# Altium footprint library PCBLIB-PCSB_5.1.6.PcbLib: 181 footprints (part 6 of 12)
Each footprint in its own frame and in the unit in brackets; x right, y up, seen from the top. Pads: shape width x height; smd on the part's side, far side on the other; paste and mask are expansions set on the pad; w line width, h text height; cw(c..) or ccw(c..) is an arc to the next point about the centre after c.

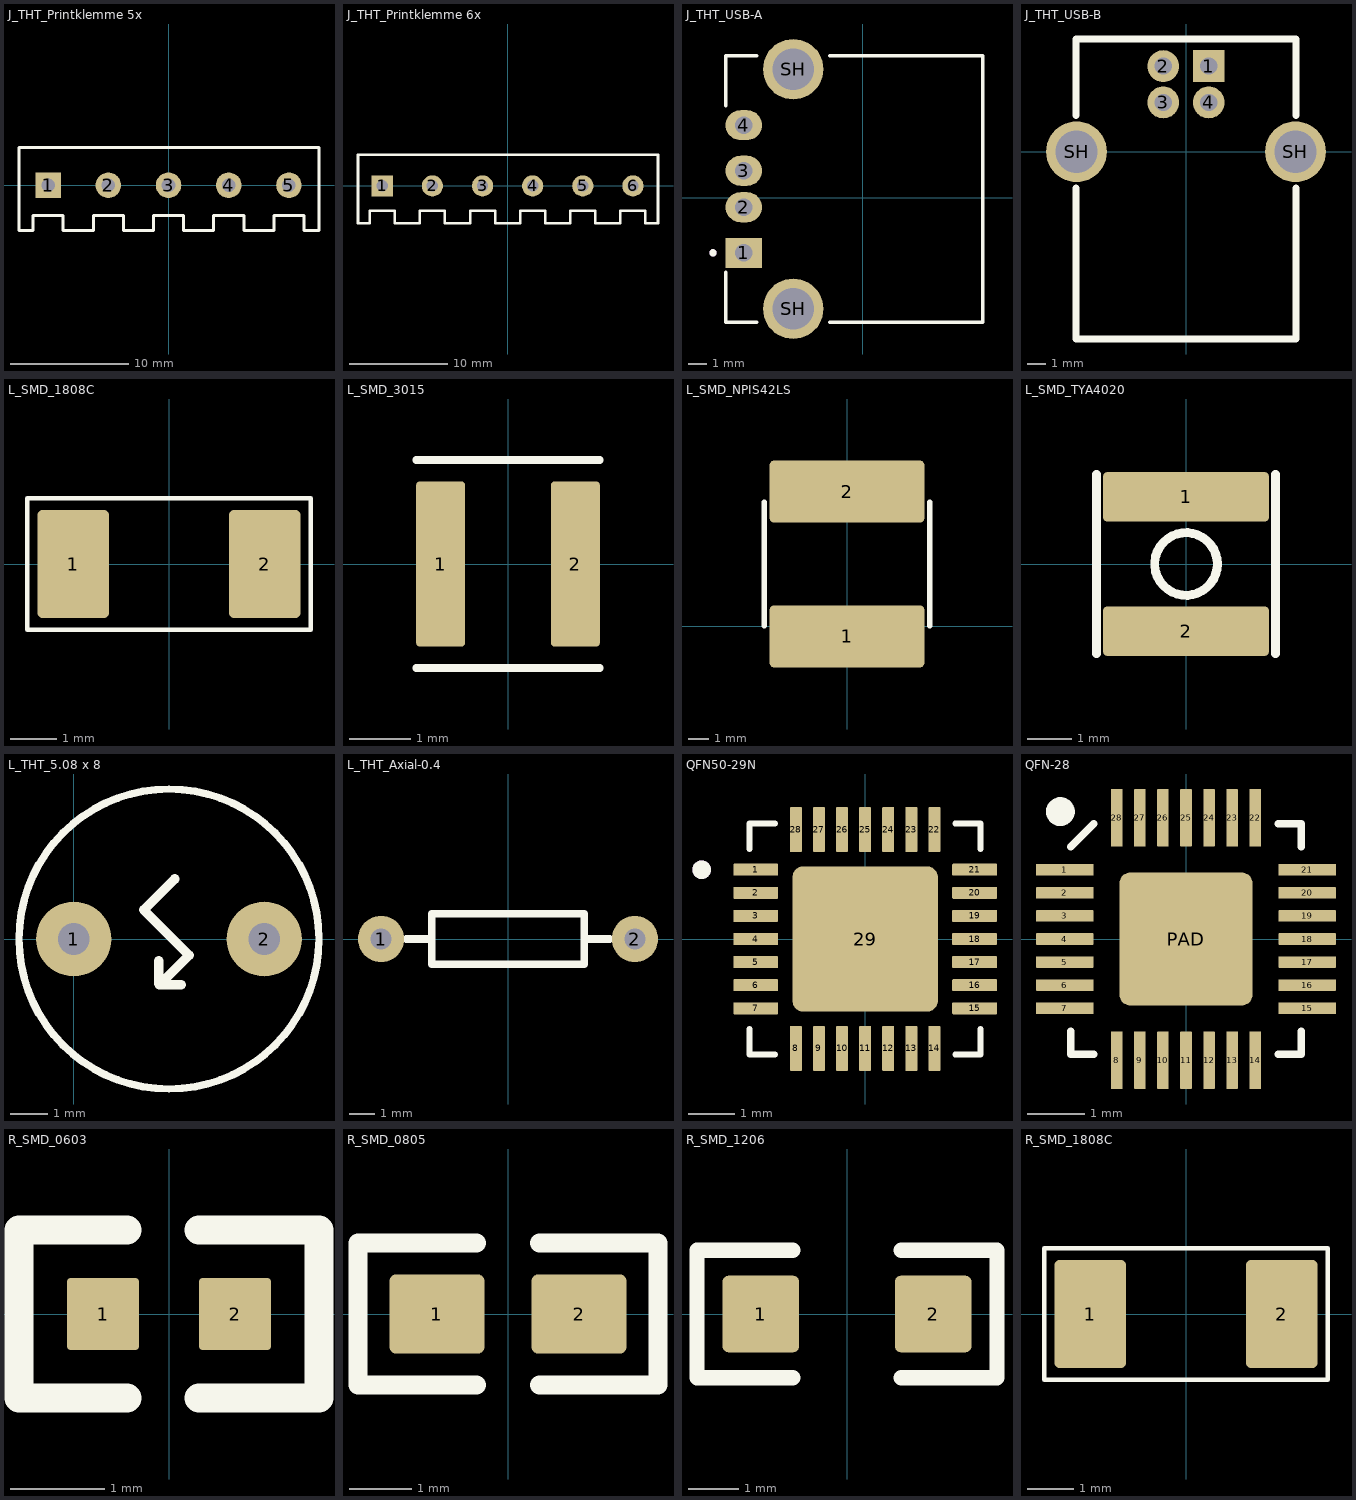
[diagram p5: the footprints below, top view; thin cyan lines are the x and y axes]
## J_THT_Printklemme 5x [mm] "LB-2024-04-17"
pads (5):
  rect 2.15x2.15 hole 1.15: 1(-10.16,0)
  round 2.15 hole 1.15: 2(-5.08,0) 3(0,0) 4(5.08,0) 5(10.16,0)
Top Overlay:
  lines w0.254: -6.35,-3.81 -6.35,-2.54 ; -6.35,-3.81 -8.89,-3.81 -8.89,-2.54 -11.43,-2.54 -11.43,-3.81 -12.62,-3.81 -12.62,2.365 -12.62,3.175 -2.43,3.175 12.7,3.175 12.7,-3.81 11.43,-3.81 11.43,-2.54 8.89,-2.54 8.89,-3.81 6.35,-3.81 6.35,-2.54 3.81,-2.54 3.81,-3.81 1.27,-3.81 1.27,-2.54 -1.27,-2.54 -1.27,-3.81 -3.81,-3.81 ; -6.35,-3.81 -6.35,-2.54 ; -6.35,-2.54 -3.81,-2.54 ; -3.81,-3.81 -3.81,-2.54 ; -3.81,-3.81 -3.81,-2.54

## J_THT_Printklemme 6x [mm] "LB-2024-04-17"
pads (6):
  rect 2.15x2.15 hole 1.15: 1(-12.7,0)
  round 2.15 hole 1.15: 2(-7.62,0) 3(-2.54,0) 4(2.54,0) 5(7.62,0) 6(12.7,0)
Top Overlay:
  lines w0.254: -8.89,-3.81 -8.89,-2.54 ; -8.89,-3.81 -11.43,-3.81 -11.43,-2.54 -13.97,-2.54 -13.97,-3.81 -15.16,-3.81 -15.16,2.365 -15.16,3.175 -4.97,3.175 15.24,3.175 15.24,-3.81 13.97,-3.81 13.97,-2.54 11.43,-2.54 11.43,-3.81 8.89,-3.81 8.89,-2.54 6.35,-2.54 6.35,-3.81 3.81,-3.81 3.81,-2.54 1.27,-2.54 1.27,-3.81 -1.27,-3.81 -1.27,-2.54 -3.81,-2.54 -3.81,-3.81 -6.35,-3.81 ; -8.89,-3.81 -8.89,-2.54 ; -8.89,-2.54 -6.35,-2.54 ; -6.35,-3.81 -6.35,-2.54 ; -6.35,-3.81 -6.35,-2.54

## J_THT_USB-A [mm] "LB-2024-04-29"
pads (6):
  rect 2x1.65 hole 0.95: 1(-6.536,-3.032)
  oval 2x1.65 hole 0.95: 2(-6.536,-0.532) 3(-6.536,1.468) 4(-6.536,3.968)
  round 3.316 hole 2.3: SH(-3.826,-6.102) SH(-3.826,7.038)
Top Overlay:
  circle w0.2: c-8.226,-3.032 r0.1
  lines w0.2: -7.526,-4.097 -7.526,-6.832 -5.836,-6.832 ; -7.526,5.033 -7.526,7.768 -5.836,7.768 ; -1.816,-6.832 6.574,-6.832 6.574,7.768 -1.816,7.768
Mechanical 13:
  circle w0.2: c-8.226,-3.032 r0.1

## J_THT_USB-B [mm] "LB-2024-04-15"
pads (6):
  rect 1.75x1.75 hole 0.95: 1(1.25,4.71)
  round 1.75 hole 0.95: 2(-1.25,4.71) 3(-1.25,2.71) 4(1.25,2.71)
  round 3.346 hole 2.33: SH(-6.02,0) SH(6.02,0)
Top Overlay:
  lines w0.4: -6.05,-2 -6.05,-10.3 6.05,-10.3 6.05,-2 ; -6.05,2 -6.05,6.2 6.05,6.2 6.05,2

## L_SMD_1808C [mm] "LB-2024-04-17"
height 2
pads (2):
  rrect15% 1.55x2.35 smd paste-0.02 mask+0.05: 1(-2.075,0) 2(2.075,0)
Top Overlay:
  lines w0.1: -3.075,-1.425 3.075,-1.425 3.075,1.425 -3.075,1.425 -3.075,-1.425

## L_SMD_3015 [mm] "LB-2024-09-01"
height 1.5
pads (2):
  rrect15% 0.8x2.7 smd paste-0.02 mask+0.05: 1(-1.1,0) 2(1.1,0)
Top Overlay:
  lines w0.127: -1.5,-1.7 1.5,-1.7 ; -1.5,1.7 1.5,1.7

## L_SMD_NPIS42LS [mm] "LB-2024-04-17"
pads (2):
  rrect15% 7.5x3 smd paste-0.02 mask+0.05: 1(0,-0.5) 2(0,6.5)
Top Overlay:
  lines w0.254: -4,0 -4,3 -4,6 ; 4,0 4,3 4,6

## L_SMD_TYA4020 [mm] "LB-2024-04-25"
height 2.1
pads (2):
  rrect15% 3.7x1.1 smd paste-0.02 mask+0.05: 1(0,1.5) 2(0,-1.5)
Top Overlay:
  circle w0.2: c0,0 r0.7
  lines w0.2: -2,-2 -2,0 -2,2 ; 2,-2 2,0 2,2

## L_THT_5.08 x 8 [mm] "LB-2024-04-17"
pads (2):
  round 2 hole 0.85: 1(0,0) 2(5.08,0)
Top Overlay:
  circle w0.2: c2.54,0 r4
  lines w0.254: 2.261,-0.762 2.261,-1.194 ; 2.261,-0.584 2.261,-1.194 ; 2.692,1.6 1.867,0.775 3.073,-0.432 2.286,-1.219 ; 2.261,-1.194 2.286,-1.219 ; 2.286,-1.219 2.87,-1.219 ; 2.286,-1.219 2.87,-1.219 ; 2.286,-1.219 2.87,-1.219

## L_THT_Axial-0.4 [mm]
pads (2):
  round 1.85 hole 0.85: 1(-5.08,0) 2(5.08,0)
Top Overlay:
  lines w0.305: -4.064,0 -3.048,0 ; 3.048,0 4.064,0 ; -3.048,-1.016 3.048,-1.016 3.048,1.016 -3.048,1.016 -3.048,-1.016

## QFN50-29N [mm] "LB-2024-09-01"
pads (29):
  rrect15% 0.97x0.26 smd paste-0.02 mask+0.05: 1(-2.37,1.5) 2(-2.37,1) 3(-2.37,0.5) 4(-2.37,0) 5(-2.37,-0.5) 6(-2.37,-1) 7(-2.37,-1.5) 15(2.37,-1.5) 16(2.37,-1) 17(2.37,-0.5) 18(2.37,0) 19(2.37,0.5) 20(2.37,1) 21(2.37,1.5)
  rrect15% 0.26x0.97 smd paste-0.02 mask+0.05: 8(-1.5,-2.37) 9(-1,-2.37) 10(-0.5,-2.37) 11(0,-2.37) 12(0.5,-2.37) 13(1,-2.37) 14(1.5,-2.37) 22(1.5,2.37) 23(1,2.37) 24(0.5,2.37) 25(0,2.37) 26(-0.5,2.37) 27(-1,2.37) 28(-1.5,2.37)
  rrect15% 3.15x3.15 smd paste-0.02 mask+0.05: 29(0,0)
Top Overlay:
  circle w0.2: c-3.54,1.5 r0.1
  lines w0.127: -2.5,-1.95 -2.5,-2.5 -1.95,-2.5 ; -2.5,1.95 -2.5,2.5 -1.95,2.5 ; 1.95,-2.5 2.5,-2.5 2.5,-1.95 ; 1.95,2.5 2.5,2.5 2.5,1.95
Mechanical 13:
  circle w0.2: c-3.54,1.5 r0.1

## QFN-28 [mm] "LB-2024-09-01"
pads (29):
  rrect15% 1x0.2 smd paste-0.02 mask+0.05: 1(-2.1,1.2) 2(-2.1,0.8) 3(-2.1,0.4) 4(-2.1,0) 5(-2.1,-0.4) 6(-2.1,-0.8) 7(-2.1,-1.2) 15(2.1,-1.2) 16(2.1,-0.8) 17(2.1,-0.4) 18(2.1,0) 19(2.1,0.4) 20(2.1,0.8) 21(2.1,1.2)
  rrect15% 0.2x1 smd paste-0.02 mask+0.05: 8(-1.2,-2.1) 9(-0.8,-2.1) 10(-0.4,-2.1) 11(0,-2.1) 12(0.4,-2.1) 13(0.8,-2.1) 14(1.2,-2.1) 22(1.2,2.1) 23(0.8,2.1) 24(0.4,2.1) 25(0,2.1) 26(-0.4,2.1) 27(-0.8,2.1) 28(-1.2,2.1)
  rrect15% 2.3x2.3 smd paste-0.02 mask+0.05: PAD(0,0)
Top Overlay:
  circle w0.3: c-2.178,2.208 r0.1
  lines w0.127: -2,-1.6 -2,-2 -1.6,-2 ; -2,1.6 -1.6,2 ; 1.6,-2 2,-2 2,-1.6 ; 1.6,2 2,2 2,1.6
Top Paste:
  region: -0.9,0.9 -0.4,0.9 -0.4,0.4 -0.9,0.4
  region: 0.4,0.9 0.9,0.9 0.9,0.4 0.4,0.4
  region: 0.4,-0.4 0.9,-0.4 0.9,-0.9 0.4,-0.9
  region: -0.9,-0.4 -0.4,-0.4 -0.4,-0.9 -0.9,-0.9

## R_SMD_0603 [mil] "LB-2024-04-17"
pads (2):
  rrect10% 30x30 smd paste-0.79 mask+1.97: 1(-27.5,0) 2(27.5,0)
Top Overlay:
  lines w12: -17.5,-35 -62.5,-35 -62.5,35 -17.5,35 ; 12.5,-35 62.5,-35 62.5,35 12.5,35

## R_SMD_0805 [mil] "LB-2024-04-17"
pads (2):
  rrect15% 60x50 smd paste-0.79 mask+1.97: 1(-45,0) 2(45,0)
Top Overlay:
  lines w12: -20,-45 -95,-45 -95,45 -20,45 ; 20,-45 95,-45 95,45 20,45

## R_SMD_1206 [mil] "LB-2024-04-17"
pads (2):
  rrect15% 60x60 smd paste-0.79 mask+1.97: 1(-67.5,0) 2(67.5,0)
Top Overlay:
  lines w12: -42.5,-50 -117.5,-50 -117.5,50 -42.5,50 ; 42.5,-50 117.5,-50 117.5,50 42.5,50

## R_SMD_1808C [mm] "LB-2024-04-17"
height 2
pads (2):
  rrect15% 1.55x2.35 smd paste-0.02 mask+0.05: 1(-2.075,0) 2(2.075,0)
Top Overlay:
  lines w0.1: -3.075,-1.425 -3.075,1.425 3.075,1.425 3.075,-1.425 -3.075,-1.425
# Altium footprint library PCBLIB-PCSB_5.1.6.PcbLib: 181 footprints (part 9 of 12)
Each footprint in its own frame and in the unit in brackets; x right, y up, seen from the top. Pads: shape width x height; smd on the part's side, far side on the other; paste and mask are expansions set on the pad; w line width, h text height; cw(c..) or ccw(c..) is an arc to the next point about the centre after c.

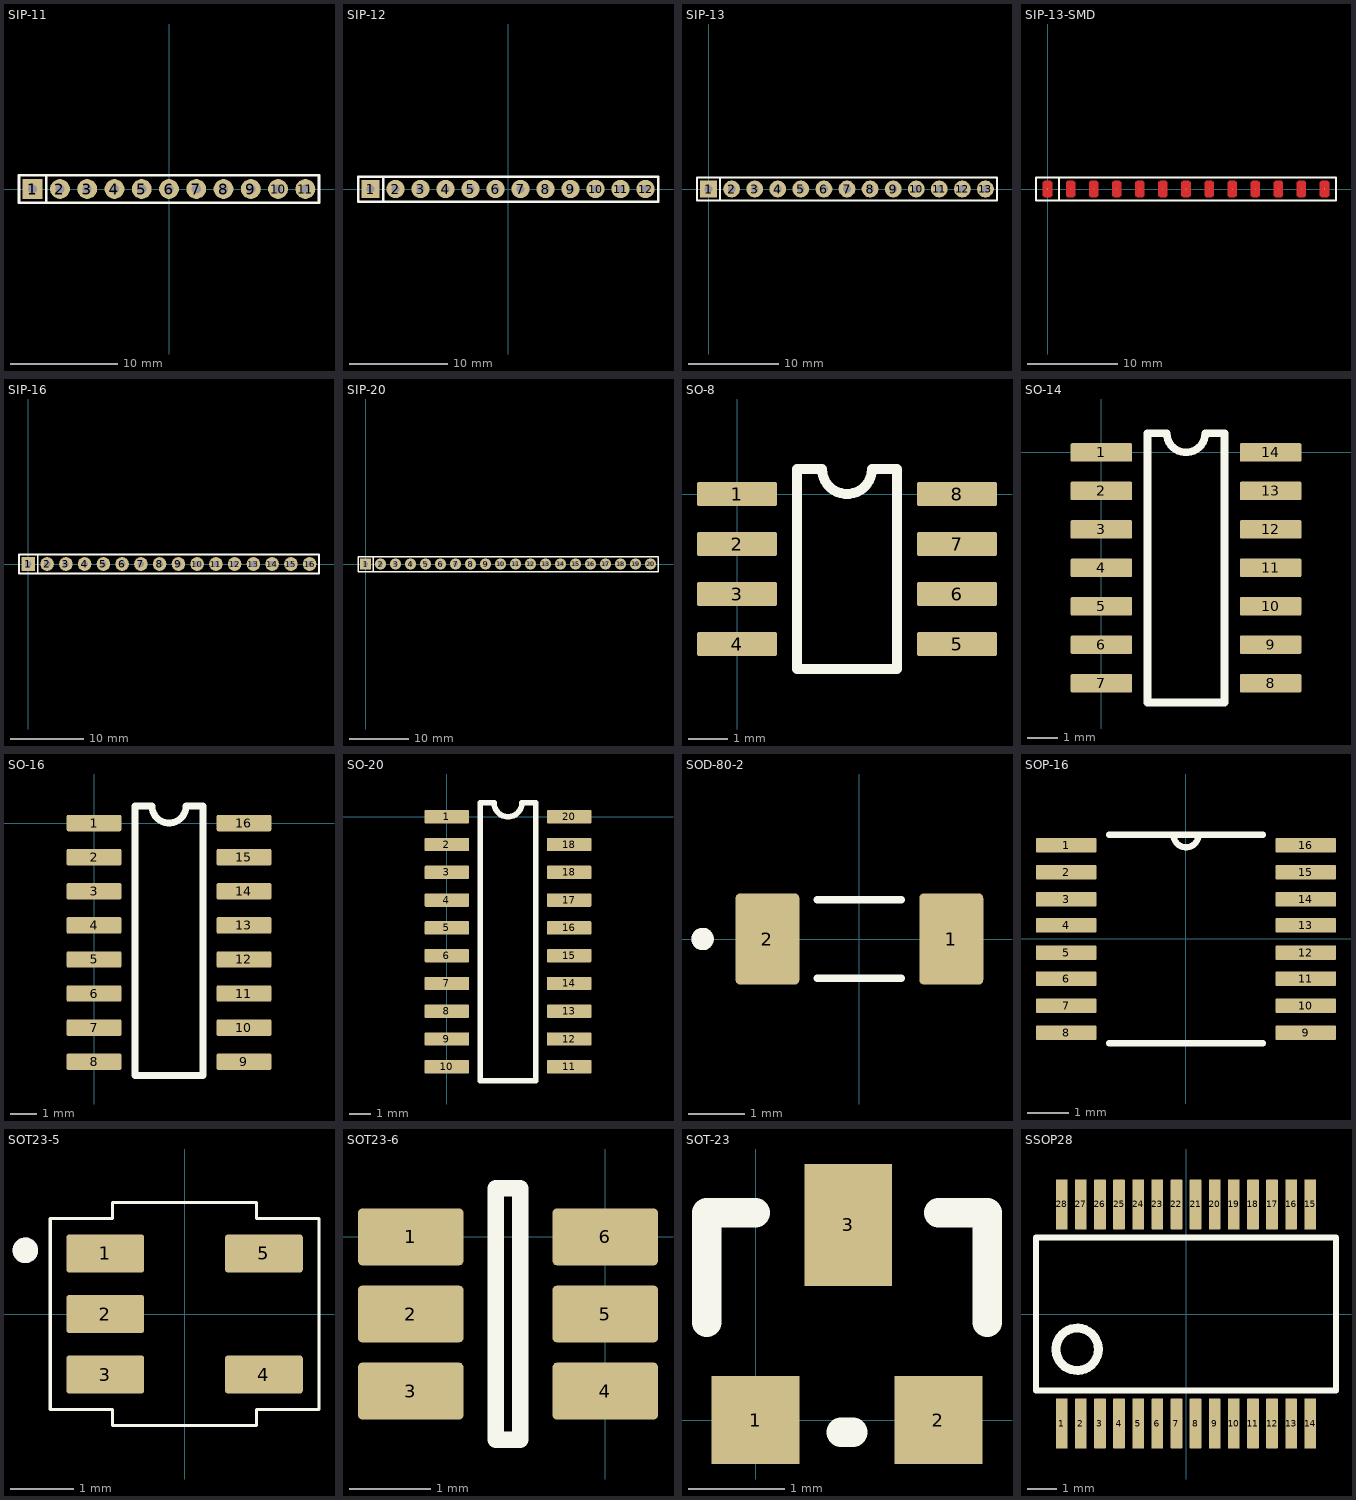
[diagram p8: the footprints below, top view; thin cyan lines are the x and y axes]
## SIP-11 [mm] "LB-2024-04-17"
pads (11):
  rect 1.85x1.85 hole 0.85: 1(-12.7,0)
  round 1.85 hole 0.85: 2(-10.16,0) 3(-7.62,0) 4(-5.08,0) 5(-2.54,0) 6(0,0) 7(2.54,0) 8(5.08,0) 9(7.62,0) 10(10.16,0) 11(12.7,0)
Top Overlay:
  lines w0.254: -11.43,-1.27 -11.43,1.27 ; -13.97,-1.27 -13.97,1.27 13.97,1.27 13.97,-1.27 -13.97,-1.27

## SIP-12 [mm] "LB-2024-04-17"
pads (12):
  rect 1.85x1.85 hole 0.85: 1(-13.97,0)
  round 1.85 hole 0.85: 2(-11.43,0) 3(-8.89,0) 4(-6.35,0) 5(-3.81,0) 6(-1.27,0) 7(1.27,0) 8(3.81,0) 9(6.35,0) 10(8.89,0) 11(11.43,0) 12(13.97,0)
Top Overlay:
  lines w0.254: -12.7,-1.27 -12.7,1.27 ; -15.24,-1.27 15.24,-1.27 15.24,1.27 -15.24,1.27 -15.24,-1.27

## SIP-13 [mm] "LB-2024-04-17"
pads (13):
  rect 1.85x1.85 hole 0.85: 1(0,0)
  round 1.85 hole 0.85: 2(2.54,0) 3(5.08,0) 4(7.62,0) 5(10.16,0) 6(12.7,0) 7(15.24,0) 8(17.78,0) 9(20.32,0) 10(22.86,0) 11(25.4,0) 12(27.94,0) 13(30.48,0)
Top Overlay:
  lines w0.254: 1.27,-1.27 1.27,1.27 ; -1.27,-1.27 -1.27,1.27 31.75,1.27 31.75,-1.27 -1.27,-1.27

## SIP-13-SMD [mil] "LB-2024-04-17"
pads (13):
  round 1 smd: 1(0,0) 2(100,0) 3(200,0) 4(300,0) 5(400,0) 6(500,0) 7(600,0) 8(700,0) 9(800,0) 10(900,0) 11(1000,0) 12(1100,0) 13(1200,0)
Top Layer:
  region: 680.31,-28.54 688.19,-36.42 711.81,-36.42 719.69,-28.54 719.69,28.54 711.81,36.42 688.19,36.42 680.31,28.54
  region: 580.31,-28.54 588.19,-36.42 611.81,-36.42 619.69,-28.54 619.69,28.54 611.81,36.42 588.19,36.42 580.31,28.54
  region: 480.31,-28.54 488.19,-36.42 511.81,-36.42 519.69,-28.54 519.69,28.54 511.81,36.42 488.19,36.42 480.31,28.54
  region: 380.31,-28.54 388.19,-36.42 411.81,-36.42 419.69,-28.54 419.69,28.54 411.81,36.42 388.19,36.42 380.31,28.54
  region: -19.69,-28.54 -11.81,-36.42 11.81,-36.42 19.69,-28.54 19.69,28.54 11.81,36.42 -11.81,36.42 -19.69,28.54
  region: 80.31,-28.54 88.19,-36.42 111.81,-36.42 119.69,-28.54 119.69,28.54 111.81,36.42 88.19,36.42 80.31,28.54
  region: 180.31,-28.54 188.19,-36.42 211.81,-36.42 219.69,-28.54 219.69,28.54 211.81,36.42 188.19,36.42 180.31,28.54
  region: 280.31,-28.54 288.19,-36.42 311.81,-36.42 319.69,-28.54 319.69,28.54 311.81,36.42 288.19,36.42 280.31,28.54
  region: 780.31,-28.54 788.19,-36.42 811.81,-36.42 819.69,-28.54 819.69,28.54 811.81,36.42 788.19,36.42 780.31,28.54
  region: 880.31,-28.54 888.19,-36.42 911.81,-36.42 919.69,-28.54 919.69,28.54 911.81,36.42 888.19,36.42 880.31,28.54
  region: 980.31,-28.54 988.19,-36.42 1011.81,-36.42 1019.69,-28.54 1019.69,28.54 1011.81,36.42 988.19,36.42 980.31,28.54
  region: 1080.31,-28.54 1088.19,-36.42 1111.81,-36.42 1119.69,-28.54 1119.69,28.54 1111.81,36.42 1088.19,36.42 1080.31,28.54
  region: 1180.31,-28.54 1188.19,-36.42 1211.81,-36.42 1219.69,-28.54 1219.69,28.54 1211.81,36.42 1188.19,36.42 1180.31,28.54
Top Overlay:
  lines w10: 50,-50 50,50 ; -50,-50 -50,50 1250,50 1250,-50 -50,-50

## SIP-16 [mm] "LB-2024-04-17"
pads (16):
  rect 1.85x1.85 hole 0.85: 1(0,0)
  round 1.85 hole 0.85: 2(2.54,0) 3(5.08,0) 4(7.62,0) 5(10.16,0) 6(12.7,0) 7(15.24,0) 8(17.78,0) 9(20.32,0) 10(22.86,0) 11(25.4,0) 12(27.94,0) 13(30.48,0) 14(33.02,0) 15(35.56,0) 16(38.1,0)
Top Overlay:
  lines w0.254: 1.27,-1.27 1.27,1.27 ; -1.27,-1.27 39.37,-1.27 39.37,1.27 -1.27,1.27 -1.27,-1.27

## SIP-20 [mm] "LB-2024-04-17"
pads (20):
  rect 1.85x1.85 hole 0.85: 1(0,0)
  round 1.85 hole 0.85: 2(2.54,0) 3(5.08,0) 4(7.62,0) 5(10.16,0) 6(12.7,0) 7(15.24,0) 8(17.78,0) 9(20.32,0) 10(22.86,0) 11(25.4,0) 12(27.94,0) 13(30.48,0) 14(33.02,0) 15(35.56,0) 16(38.1,0) 17(40.64,0) 18(43.18,0) 19(45.72,0) 20(48.26,0)
Top Overlay:
  lines w0.254: 1.27,-1.27 1.27,1.27 ; -1.27,-1.27 49.53,-1.27 49.53,1.27 -1.27,1.27 -1.27,-1.27

## SO-8 [mil] "LB-2024-04-17"
pads (8):
  rrect15% 80x24 smd paste-0.79 mask+1.97: 1(0,0) 2(0,-50) 3(0,-100) 4(0,-150) 5(220,-150) 6(220,-100) 7(220,-50) 8(220,0)
Top Overlay:
  lines w10: 60,-175 60,25 85,25 ccw(c110,25) 135,25 160,25 160,-175 60,-175

## SO-14 [mil] "LB-2024-04-17"
pads (14):
  rrect15% 80x24 smd paste-0.79 mask+1.97: 1(0,0) 2(0,-50) 3(0,-100) 4(0,-150) 5(0,-200) 6(0,-250) 7(0,-300) 8(220,-300) 9(220,-250) 10(220,-200) 11(220,-150) 12(220,-100) 13(220,-50) 14(220,0)
Top Overlay:
  lines w10: 60,-325 160,-325 160,25 135,25 cw(c110,25) 85,25 60,25 60,-325

## SO-16 [mil] "LB-2024-04-17"
pads (16):
  rrect15% 80x24 smd paste-0.79 mask+1.97: 1(0,0) 2(0,-50) 3(0,-100) 4(0,-150) 5(0,-200) 6(0,-250) 7(0,-300) 8(0,-350) 9(220,-350) 10(220,-300) 11(220,-250) 12(220,-200) 13(220,-150) 14(220,-100) 15(220,-50) 16(220,0)
Top Overlay:
  lines w10: 60,-370 60,25 85,25 ccw(c110,25) 135,25 160,25 160,-370 60,-370

## SO-20 [mil] "LB-2024-04-17"
pads (20):
  rrect15% 80x24 smd paste-0.79 mask+1.97: 1(0,0) 2(0,-50) 3(0,-100) 4(0,-150) 5(0,-200) 6(0,-250) 7(0,-300) 8(0,-350) 9(0,-400) 10(0,-450) 11(220,-450) 12(220,-400) 13(220,-350) 14(220,-300) 15(220,-250) 16(220,-200) 17(220,-150) 18(220,-100) 18(220,-50) 20(220,0)
Top Overlay:
  lines w10: 60,-475 60,25 85,25 ccw(c110,25) 135,25 160,25 160,-475 60,-475

## SOD-80-2 [mm]
pads (2):
  rrect15% 1.14x1.63 smd paste-0.02 mask+0.05: 1(1.64,0) 2(-1.64,0)
Top Overlay:
  circle w0.2: c-2.795,0 r0.1
  lines w0.127: -0.75,-0.7 0.75,-0.7 ; -0.75,0.7 0.75,0.7
Mechanical 13:
  circle w0.2: c-2.795,0 r0.1
  lines w0.127: -1.7,-0.7 -1.7,0.7 ; 1.7,-0.7 1.7,0.7

## SOP-16 [mil] "LB-2024-04-17"
pads (16):
  rrect15% 58x14 smd paste-0.79 mask+1.97: 1(-115,90) 2(-115,64) 3(-115,38) 4(-115,13) 5(-115,-13) 6(-115,-38) 7(-115,-64) 8(-115,-90) 9(115,-90) 10(115,-64) 11(115,-38) 12(115,-13) 13(115,13) 14(115,38) 15(115,64) 16(115,90)
Top Overlay:
  lines w6: -74,-100 74,-100 ; -74,100 -12,100 ; 74,100 12,100 ; -12,100 ccw(c0,100) 12,100 ; -12,100 12,100
Mechanical 13:
  lines w0: -12,100 ccw(c0,100) 12,100

## SOT23-5 [mm]
pads (5):
  rrect15% 1.22x0.6 smd paste-0.02 mask+0.05: 1(-1.245,0.95) 2(-1.245,0) 3(-1.245,-0.95) 4(1.245,-0.95) 5(1.245,0.95)
Top Overlay:
  circle w0.2: c-2.5,1 r0.1
  lines w0.05: -2.11,-1.5 -2.11,1.5 -1.13,1.5 -1.13,1.75 1.13,1.75 1.13,1.5 2.11,1.5 2.11,-1.5 1.13,-1.5 1.13,-1.75 -1.13,-1.75 -1.13,-1.5 -2.11,-1.5
Mechanical 13:
  circle w0.2: c-2.5,1 r0.1

## SOT23-6 [mm] "LB-2024-04-25"
height 1.45
pads (6):
  rrect15% 1.3x0.7 smd paste-0.02 mask+0.05: 1(-2.4,0) 2(-2.4,-0.95) 3(-2.4,-1.9) 4(0,-1.9) 5(0,-0.95) 6(0,0)
Top Overlay:
  lines w0.2: -1.35,-2.5 -1.05,-2.5 -1.05,0.6 -1.35,0.6 -1.35,-2.5

## SOT-23 [mil]
pads (3):
  rect 36x36 smd: 1(0,0) 2(75,0)
  rect 36x50 smd: 3(38,80)
Top Overlay:
  lines w12: -20,40 -20,85 0,85 ; 35,-5 40,-5 ; 75,85 95,85 95,40

## SSOP28 [mm] "LB-2024-09-01"
pads (28):
  rrect15% 0.4x1.7 smd paste-0.02 mask+0.05: 1(-4.225,-3.725) 2(-3.575,-3.725) 3(-2.925,-3.725) 4(-2.275,-3.725) 5(-1.625,-3.725) 6(-0.975,-3.725) 7(-0.325,-3.725) 8(0.325,-3.725) 9(0.975,-3.725) 10(1.625,-3.725) 11(2.275,-3.725) 12(2.925,-3.725) 13(3.575,-3.725) 14(4.225,-3.725) 15(4.225,3.725) 16(3.575,3.725) 17(2.925,3.725) 18(2.275,3.725) 19(1.625,3.725) 20(0.975,3.725) 21(0.325,3.725) 22(-0.325,3.725) 23(-0.975,3.725) 24(-1.625,3.725) 25(-2.275,3.725) 26(-2.925,3.725) 27(-3.575,3.725) 28(-4.225,3.725)
Top Overlay:
  circle w0.3: c-3.7,-1.2 r0.721
  lines w0.203: -5.1,-2.6 -5.1,2.6 5.1,2.6 5.1,-2.6 -5.1,-2.6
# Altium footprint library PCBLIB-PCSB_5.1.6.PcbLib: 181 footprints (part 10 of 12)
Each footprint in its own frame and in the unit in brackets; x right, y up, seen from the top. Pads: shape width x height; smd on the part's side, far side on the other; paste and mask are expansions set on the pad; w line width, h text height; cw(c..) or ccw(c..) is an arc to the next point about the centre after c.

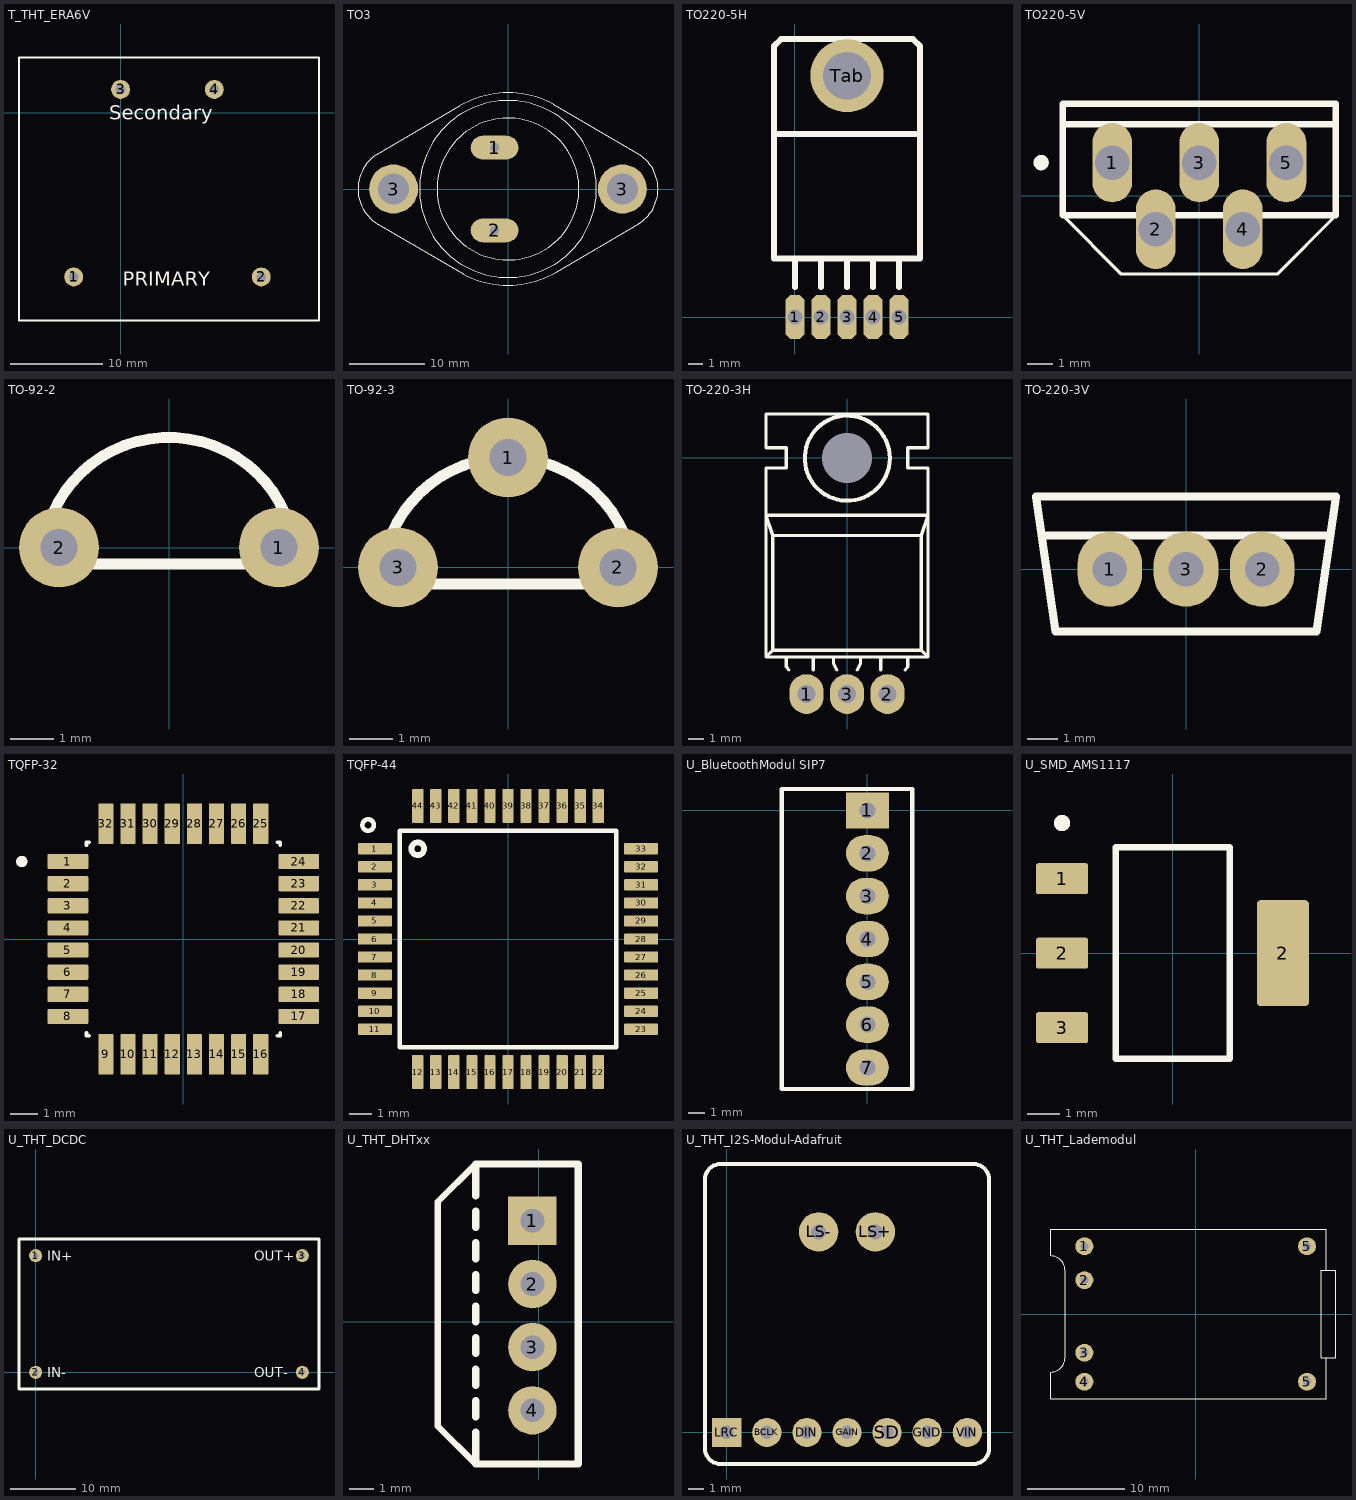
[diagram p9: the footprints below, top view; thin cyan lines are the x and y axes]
## T_THT_ERA6V [mm] "LB-2024-04-17"
pads (4):
  round 2.05 hole 1.05: 1(-5.08,-17.78) 2(15.24,-17.78) 3(0,2.54) 4(10.16,2.54)
Top Overlay:
  lines w0.254: -11,-22.5 21.5,-22.5 21.5,6 -11,6 -11,-22.5
  text "PRIMARY" at 0.254,-18.746 h1.52
  text "Secondary" at -1.246,-0.738 h1.52

## TO3 [mil] "LB-2024-04-17"
pads (4):
  oval 248x124 hole 47.05: 1(-70,215) 2(-70,-215)
  round 255 hole 162: 3(-595,0) 3(595,0)
Top Overlay:
  circle w6: c0,0 r369
  circle w2: c0,0 r460
  lines w6: -680,180 -250,433 cw(c0,0) 0,500 cw(c0,0) 234.74,441.47 ; -679,-181 -234,-442 ; -676.7,-182.58 cw(c-567,0) -780,0 cw(c-567,0) -673.5,184.46 ; -234.74,-441.47 ccw(c0,0) 0,-500 ccw(c0,0) 250,-433.01 ; 235,441 684,178 ; 251,-433 684,-178 ; 683.01,-178.64 ccw(c567,0) 780,0 ccw(c567,0) 683.01,178.64
Mechanical 13:
  circle w6: c595,0 r85
  circle w6: c-595,0 r85

## TO220-5H [mm] "LB-2024-04-19"
height 5
pads (6):
  oct 1.3x3 hole 1.05: 1(0,0) 2(1.778,0) 3(3.556,0) 4(5.334,0) 5(7.112,0)
  round 5 hole 3.25: Tab(3.556,16.5)
Top Overlay:
  lines w0.4: 0,2.032 0,4 ; 1.778,2.032 1.778,4 ; 3.556,2.032 3.556,4 ; 3.556,16.5 3.556,19 ; 5.334,2.032 5.334,4 ; 7.112,2.032 7.112,4 ; -1.444,12.5 8.556,12.5 ; -1.444,12.5 -1.444,4 8.556,4 8.556,12.5 ; -1.444,12.5 -1.444,18.5 -0.944,19 8.056,19 8.556,18.5 ; 8.556,12.5 8.556,18.5 ; 8.556,18.5 8.556,18.5

## TO220-5V [mm] "LB-2024-0419"
height 16.51
pads (5):
  oval 1.55x3.1 hole 1.35: 1(-3.4,1.3) 2(-1.7,-1.3) 3(0,1.3) 4(1.7,-1.3) 5(3.4,1.3)
Top Overlay:
  circle w0.2: c-6.175,1.3 r0.2
  rectangle: -6.325,1.15 -5.975,1.5
  lines w0.127: -5.335,-0.761 -3.048,-3.048 3.048,-3.048 5.335,-0.761 5.335,3.59 -5.335,3.59 -5.335,-0.761
  lines w0.254: -5.334,2.794 5.334,2.794 ; 5.334,2.794 5.334,-0.762 -5.334,-0.762 -5.334,3.589 -5.335,3.59 5.333,3.59 5.334,3.589 5.334,2.794

## TO-92-2 [mm] "LB-2024-04-18"
pads (2):
  round 1.85 hole 0.85: 1(2.54,0) 2(-2.54,0)
Top Overlay:
  lines w0.254: -2.927,-0.381 cw(c-0.003,-0.381) 2.921,-0.381 -2.927,-0.381

## TO-92-3 [mm] "LB-2024-04-17"
pads (3):
  round 1.85 hole 0.85: 1(0,2.54) 2(2.54,0) 3(-2.54,0)
Top Overlay:
  lines w0.254: -2.927,-0.381 cw(c-0.003,-0.381) 2.921,-0.381 -2.927,-0.381

## TO-220-3H [mm] "LB-2024-04-17"
pads (4):
  round 0 hole 3.15: 0(0,0)
  oval 2.15x2.5 hole 1.15: 1(-2.54,-14.817) 2(2.54,-14.817) 3(0,-14.817)
Top Overlay:
  circle w0.254: c0.017,-0.02 r2.667
  lines w0.2: -3.81,-13.123 -3.81,-12.488 ; -3.762,-13.155 -3.647,-13.317 ; -2.117,-13.317 -2.117,-12.488 ; -0.847,-12.488 -0.847,-12.912 -0.635,-13.317 ; 0.635,-13.317 0.847,-12.912 0.847,-12.488 ; 2.117,-13.317 2.117,-12.488 ; 3.655,-13.317 3.818,-13.099 ; 3.81,-13.123 3.81,-12.488 ; -5.08,-12.488 -5.08,-0.635 -3.81,-0.635 -3.81,0.635 -5.08,0.635 -5.08,2.752 5.08,2.752 5.08,0.635 3.81,0.635 3.81,-0.635 5.08,-0.635 5.08,-12.488 ; -5.08,-12.488 5.08,-12.488 ; -5.08,-12.488 -4.657,-12.065 ; -4.657,-12.065 -4.657,-4.868 ; -4.657,-12.065 4.657,-12.065 ; -4.657,-4.868 -5.08,-3.598 5.08,-3.598 4.657,-4.868 ; -4.657,-4.868 4.657,-4.868 ; 4.657,-12.065 4.657,-4.868 ; 4.657,-12.065 5.08,-12.488

## TO-220-3V [mm] "LB-2024-04-17"
pads (3):
  oval 2.15x2.5 hole 1.15: 1(-2.54,0) 2(2.54,0) 3(0,0)
Top Overlay:
  lines w0.254: -4.812,1.125 4.808,1.125 ; -5,2.425 -4.35,-2.075 0,-2.075 4.35,-2.075 5,2.425 0,2.425 -5,2.425

## TQFP-32 [mm] "LB-2024-04-19"
height 1.2
pads (32):
  rrect15% 1.47x0.55 smd paste-0.02 mask+0.05: 1(-4.17,2.8) 2(-4.17,2) 3(-4.17,1.2) 4(-4.17,0.4) 5(-4.17,-0.4) 6(-4.17,-1.2) 7(-4.17,-2) 8(-4.17,-2.8) 17(4.17,-2.8) 18(4.17,-2) 19(4.17,-1.2) 20(4.17,-0.4) 21(4.17,0.4) 22(4.17,1.2) 23(4.17,2) 24(4.17,2.8)
  rrect15% 0.55x1.47 smd paste-0.02 mask+0.05: 9(-2.8,-4.17) 10(-2,-4.17) 11(-1.2,-4.17) 12(-0.4,-4.17) 13(0.4,-4.17) 14(1.2,-4.17) 15(2,-4.17) 16(2.8,-4.17) 25(2.8,4.17) 26(2,4.17) 27(1.2,4.17) 28(0.4,4.17) 29(-0.4,4.17) 30(-1.2,4.17) 31(-2,4.17) 32(-2.8,4.17)
Top Overlay:
  circle w0.2: c-5.84,2.8 r0.1
  lines w0.127: -3.5,-3.395 -3.5,-3.5 -3.395,-3.5 ; -3.5,3.395 -3.5,3.5 -3.395,3.5 ; 3.395,-3.5 3.5,-3.5 3.5,-3.395 ; 3.395,3.5 3.5,3.5 3.5,3.395
Mechanical 13:
  circle w0.2: c-5.84,2.8 r0.1

## TQFP-44 [mm] "LB-2024-06-15"
pads (44):
  rrect15% 1.5x0.5 smd paste-0.02 mask+0.05: 1(-5.9,4) 2(-5.9,3.2) 3(-5.9,2.4) 4(-5.9,1.6) 5(-5.9,0.8) 6(-5.9,0) 7(-5.9,-0.8) 8(-5.9,-1.6) 9(-5.9,-2.4) 10(-5.9,-3.2) 11(-5.9,-4) 23(5.9,-4) 24(5.9,-3.2) 25(5.9,-2.4) 26(5.9,-1.6) 27(5.9,-0.8) 28(5.9,0) 29(5.9,0.8) 30(5.9,1.6) 31(5.9,2.4) 32(5.9,3.2) 33(5.9,4)
  rrect15% 0.5x1.5 smd paste-0.02 mask+0.05: 12(-4,-5.9) 13(-3.2,-5.9) 14(-2.4,-5.9) 15(-1.6,-5.9) 16(-0.8,-5.9) 17(0,-5.9) 18(0.8,-5.9) 19(1.6,-5.9) 20(2.4,-5.9) 21(3.2,-5.9) 22(4,-5.9) 34(4,5.9) 35(3.2,5.9) 36(2.4,5.9) 37(1.6,5.9) 38(0.8,5.9) 39(0,5.9) 40(-0.8,5.9) 41(-1.6,5.9) 42(-2.4,5.9) 43(-3.2,5.9) 44(-4,5.9)
Top Overlay:
  circle w0.254: c-4,4 r0.283
  circle w0.2: c-6.2,5.05 r0.254
  lines w0.203: -4.8,-4.8 4.8,-4.8 4.8,4.8 -4.8,4.8 -4.8,-4.8

## U_BluetoothModul SIP7 [mm] "LB-2024-04-19"
pads (7):
  rect 2.54x2.15 hole 0.95: 1(0,0)
  oval 2.54x2.15 hole 0.95: 2(0,-2.54) 3(0,-5.08) 4(0,-7.62) 5(0,-10.16) 6(0,-12.7) 7(0,-15.24)
Top Overlay:
  lines w0.254: -5.08,-16.51 2.667,-16.51 2.667,1.27 -5.08,1.27 -5.08,-16.51

## U_SMD_AMS1117 [mm] "LB-2024-04-17"
pads (4):
  rrect15% 1.604x0.952 smd paste-0.02 mask+0.05: 1(-3.395,2.29) 2(-3.395,0) 3(-3.395,-2.29)
  rrect15% 1.604x3.262 smd paste-0.02 mask+0.05: 2(3.395,0)
Top Overlay:
  circle w0.25: c-3.395,4 r0.125
  lines w0.2: -1.753,-3.253 1.753,-3.253 1.753,3.253 -1.753,3.253 -1.753,-3.253
Mechanical 5:

## U_THT_DCDC [mm] "LB-2024-04-17"
pads (4):
  round 2 hole 0.85: 1(0,17.78) 2(0,0) 3(40.64,17.78) 4(40.64,0)
Top Overlay:
  lines w0.4: -2.54,-2.54 -2.54,20.32 43.18,20.32 43.18,-2.54 -2.54,-2.54
  text "IN+" at 1.778,17.018 h1.52
  text "IN-" at 1.778,-0.762 h1.52
  text "OUT+" at 33.274,17.018 h1.52
  text "OUT-" at 33.274,-0.762 h1.52

## U_THT_DHTxx [mm] "LB-2024-04-19"
pads (4):
  rect 1.95x1.95 hole 0.95: 1(-0.254,4.064)
  round 1.95 hole 0.95: 2(-0.254,1.524) 3(-0.254,-1.016) 4(-0.254,-3.556)
Top Overlay:
  lines w0.254: -2.54,-5.715 -4.064,-4.191 -4.064,4.826 -2.54,6.35
  lines w0.3: -2.54,-4.445 -2.54,-5.715 1.59,-5.715 1.59,6.35 -2.54,6.35 -2.54,5.08 ; -2.54,-3.81 -2.54,-3.175 ; -2.54,-2.54 -2.54,-1.905 ; -2.54,-1.27 -2.54,-0.635 ; -2.54,0 -2.54,0.635 ; -2.54,1.27 -2.54,1.905 ; -2.54,2.54 -2.54,3.175 ; -2.54,3.81 -2.54,4.445

## U_THT_I2S-Modul-Adafruit [mm] "LB-2024-05-02"
pads (9):
  round 1.85 hole 0.85: BCLK(2.54,0) DIN(5.08,0) GAIN(7.62,0) GND(12.7,0) SD(10.16,0) VIN(15.24,0)
  rect 1.85x1.85 hole 0.85: LRC(0,0)
  round 2.5 hole 0.95: LS+(9.42,12.7) LS-(5.82,12.7)
Top Overlay:
  lines w0.254: -1.38,-1 ccw(c-0.38,-1) -0.38,-2 7.62,-2 15.62,-2 ccw(c15.62,-1) 16.62,-1 16.62,16 ccw(c15.62,16) 15.62,17 -0.38,17 ccw(c-0.38,16) -1.38,16 -1.38,-1

## U_THT_Lademodul [mm] "LB-2024-04-25"
pads (6):
  round 1.85 hole 0.85: 1(-11.5,7) 2(-11.5,3.5) 3(-11.5,-4) 4(-11.5,-7) 5(11.5,-7) 5(11.5,7)
Top Overlay:
  lines w0.127: 13.5,-4.5 13.5,-8.75 -15,-8.75 -15,-6 ccw(c-15,-4.5) -13.5,-4.5 -13.5,4.5 ccw(c-15,4.5) -15,6 ; 13.5,4.5 13.5,8.75 -15,8.75 -15,6 ; -15,6 -15,6 ; 13,-4.5 13,0 13,4.5 14.5,4.5 14.5,-4.5 13,-4.5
